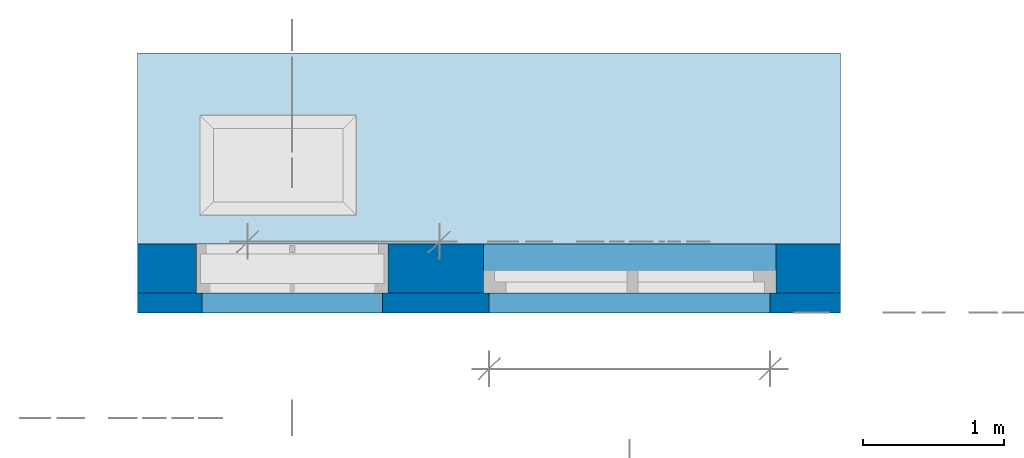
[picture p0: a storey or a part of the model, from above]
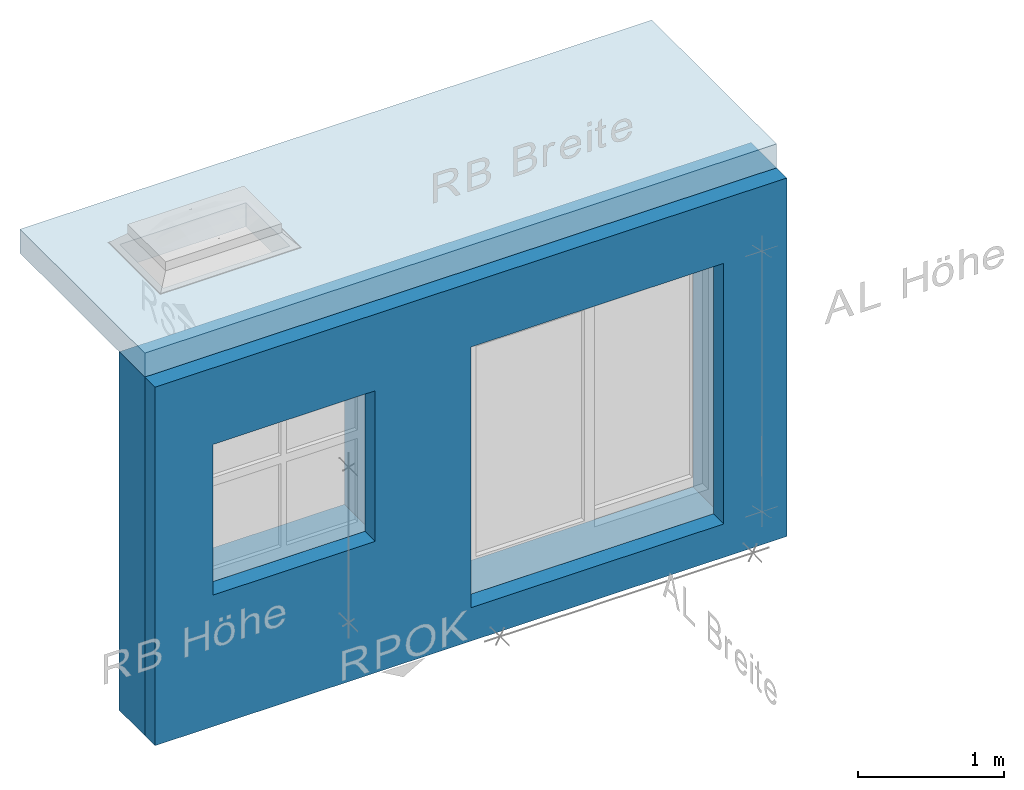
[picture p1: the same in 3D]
Properties of the parts of a building model (IFC4)

# File
Description: no view
File name: ÖBV_OEBV_Richtlinie_Fenster_Fenstertüren_Lichtkuppeln.ifc
Time: 2024-03-13T09:51:08
Author: Oesterreichische Bautechnik Vereinigung
Organization: OEBV
Written by: ODA SDAI 24.5
Authorization: OEBV

# IfcSite, Liegenschaft
RefLatitude: 48, 8, 10, 320000; RefLongitude: 11, 41, 19, 320000

# IfcBuildingStorey, Geschoss 01
In: Gebäude
Elevation: 0 m

# IfcBuildingElementProxy (10)
In: Geschoss 01
Name | Allright_Bauteil_ID
RPOK | 0023Mak0000181879
RSTUK | 0023Mak0000182013
macro | 0023Mak0000181846
macro | 0023Mak0000181868
macro | 0023Mak0000189761
macro | 0023Mak0000189774
macro | 0023Mak0000189785
macro | 0023Mak0000189809
macro | 0023Mak0000189831
macro | 0023Mak0000189846

# IfcElementAssembly (11)
In: Geschoss 01
Name | Allright_Bauteil_ID
SpatialDim_Group | 0023Elg0000181880
SpatialDim_Group | 0023Elg0000181913
WA_01
SpatialDim_Group | 0023Elg0000181847
SpatialDim_Group | 0023Elg0000181869
SpatialDim_Group | 0023Elg0000181935
SpatialDim_Group | 0023Elg0000181959
SpatialDim_Group | 0023Elg0000189786
SpatialDim_Group | 0023Elg0000189810
SpatialDim_Group | 0023Elg0000189832
SpatialDim_Group | 0023Elg0000189847

# IfcOpeningElement, DDB_01
In: Geschoss 01
Description: Deckendurchbruch; PredefinedType: OPENING
AllplanAttributes - Object Layer Attributes #1, Allright_Bauteil_ID: 0023Ddu0000177210

# IfcOpeningElement: Opening (4)
In: Geschoss 01
Name | Allright_Bauteil_ID
Fensteröffnung | 0023Fen0000176663
Fensteröffnung | 0023Fen0000177910
Fensteröffnung | 0023Fen0000188901
Fensteröffnung | 0023Fen0000188820

# IfcSlab, WA_01
In: Geschoss 01
Description: Innenwand; PredefinedType: FLOOR; Material: C25/30
AllplanAttributes - Allright_Bauteil_ID: 0023De 0000177203

# IfcWall (2)
In: Geschoss 01
Name | Description | Material | Allright_Bauteil_ID
WA_01 | Wärmedämmung | Dämmstoff hart | 0023Wa 0000000004
WA_01 | Außenwand | C20/25 | 0023Wa 0000188813

# IfcWindow (3)
In: Geschoss 01
Name | OverallHeight (m) | OverallWidth (m) | PredefinedType | Material
Fenster | 2.22 | 2.08 | USERDEFINED | Kunststoff | AllplanAttributes (Fenster) - Allright_Bauteil_ID: 0023Mak0000176674
FE_01 | 1.3 | 1.365 | USERDEFINED | Holz weiß lackiert | Description: Fenster; AllplanAttributes (FE_01) - Allright_Bauteil_ID: 0023Mak0000179185
Lichtkuppel | 0.2 | 1 | SKYLIGHT | PartitioningType: USERDEFINED; AllplanAttributes (Lichtkuppel) - Allright_Bauteil_ID: 0023Mak0000177268
